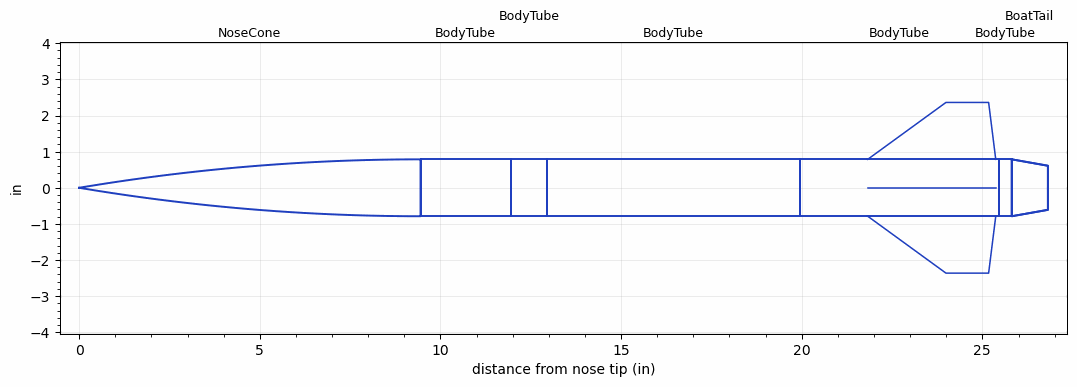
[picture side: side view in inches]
<RASAeroDocument>
 <FileVersion>2</FileVersion>
 <RocketDesign>
  <NoseCone>
   <Length>9.4488</Length>
   <Diameter>1.5748</Diameter>
   <Shape>Tangent Ogive</Shape>
   <Location>0</Location>
  </NoseCone>
  <BodyTube>
   <Length>2.5</Length>
   <Diameter>1.5748</Diameter>
   <Location>9.4488</Location>
  </BodyTube>
  <BodyTube>
   <Length>1</Length>
   <Diameter>1.5748</Diameter>
   <Location>11.9488</Location>
  </BodyTube>
  <BodyTube>
   <Length>7</Length>
   <Diameter>1.5748</Diameter>
   <Location>12.9488</Location>
  </BodyTube>
  <BodyTube>
   <Length>5.5</Length>
   <Diameter>1.5748</Diameter>
   <Location>19.9488</Location>
   <Fin>
    <Count>4</Count>
    <Chord>3.5433</Chord>
    <Span>1.5748</Span>
    <SweepDistance>2.1653</SweepDistance>
    <TipChord>1.1811</TipChord>
    <Thickness>0.1181</Thickness>
    <Location>3.622</Location>
    <AirfoilSection>Subsonic NACA</AirfoilSection>
   </Fin>
  </BodyTube>
  <BodyTube>
   <Length>0.365</Length>
   <Diameter>1.5748</Diameter>
   <Location>25.4488</Location>
   <BoattailLength>1</BoattailLength>
   <BoattailRearDiameter>1.2205</BoattailRearDiameter>
  </BodyTube>
  <BoatTail>
   <Length>1</Length>
   <Diameter>1.5748</Diameter>
   <RearDiameter>1.2205</RearDiameter>
   <Location>25.8138</Location>
  </BoatTail>
  <Surface>Rough Camouflage Paint</Surface>
  <ModifiedBarrowman>True</ModifiedBarrowman>
  <Turbulence>True</Turbulence>
  <UseBooster1>False</UseBooster1>
  <UseBooster2>False</UseBooster2>
 </RocketDesign>
 <LaunchSite>
  <Altitude>2000</Altitude>
  <Pressure>29.92</Pressure>
  <RodAngle>0</RodAngle>
  <RodLength>6</RodLength>
  <Temperature>59</Temperature>
  <WindSpeed>4.47</WindSpeed>
 </LaunchSite>
 <Recovery>
  <Altitude1>0</Altitude1>
  <Altitude2>0</Altitude2>
  <DeviceType1>None</DeviceType1>
  <DeviceType2>None</DeviceType2>
  <Event1>False</Event1>
  <Event2>False</Event2>
  <Size1>0</Size1>
  <Size2>0</Size2>
  <EventType1>None</EventType1>
  <EventType2>None</EventType2>
  <CD1>0</CD1>
  <CD2>0</CD2>
 </Recovery>
 <SimulationList>
  <Simulation>
   <SustainerEngine>I245G  (AT)</SustainerEngine>
   <SustainerLaunchWt>1.79</SustainerLaunchWt>
   <SustainerNozzleDiameter>0.5</SustainerNozzleDiameter>
   <SustainerCG>17.11</SustainerCG>
   <SustainerIgnitionDelay>0</SustainerIgnitionDelay>
   <Booster1SeparationDelay>0</Booster1SeparationDelay>
   <Booster1IgnitionDelay>0</Booster1IgnitionDelay>
   <IncludeBooster1>False</IncludeBooster1>
   <Booster2Delay>0</Booster2Delay>
   <IncludeBooster2>False</IncludeBooster2>
   <TimetoApogee>18.68033</TimetoApogee>
   <MaxAltitude>8029.072</MaxAltitude>
   <MaxVelocity>1317.465</MaxVelocity>
   <OptimumWt>1.79</OptimumWt>
   <OptimumMaxAlt>1.79</OptimumMaxAlt>
  </Simulation>
  <Simulation>
   <SustainerLaunchWt>2.3643</SustainerLaunchWt>
   <SustainerCG>16.4358</SustainerCG>
   <SustainerIgnitionDelay>0</SustainerIgnitionDelay>
   <Booster1SeparationDelay>0</Booster1SeparationDelay>
   <Booster1IgnitionDelay>0</Booster1IgnitionDelay>
   <IncludeBooster1>False</IncludeBooster1>
   <Booster2Delay>0</Booster2Delay>
   <IncludeBooster2>False</IncludeBooster2>
  </Simulation>
  <Simulation>
   <SustainerLaunchWt>2.3364</SustainerLaunchWt>
   <SustainerCG>16.5268</SustainerCG>
   <SustainerIgnitionDelay>0</SustainerIgnitionDelay>
   <Booster1SeparationDelay>0</Booster1SeparationDelay>
   <Booster1IgnitionDelay>0</Booster1IgnitionDelay>
   <IncludeBooster1>False</IncludeBooster1>
   <Booster2Delay>0</Booster2Delay>
   <IncludeBooster2>False</IncludeBooster2>
  </Simulation>
  <Simulation>
   <SustainerLaunchWt>2.3808</SustainerLaunchWt>
   <SustainerCG>16.5694</SustainerCG>
   <SustainerIgnitionDelay>0</SustainerIgnitionDelay>
   <Booster1SeparationDelay>0</Booster1SeparationDelay>
   <Booster1IgnitionDelay>0</Booster1IgnitionDelay>
   <IncludeBooster1>False</IncludeBooster1>
   <Booster2Delay>0</Booster2Delay>
   <IncludeBooster2>False</IncludeBooster2>
  </Simulation>
 </SimulationList>
</RASAeroDocument>
